# Generated deterministically by seda-macro-lef-normalizer-v1; recipe orfs-asap7-fakeram-m4-v1.
VERSION 5.8 ;
BUSBITCHARS "[]" ;
DIVIDERCHAR "/" ;

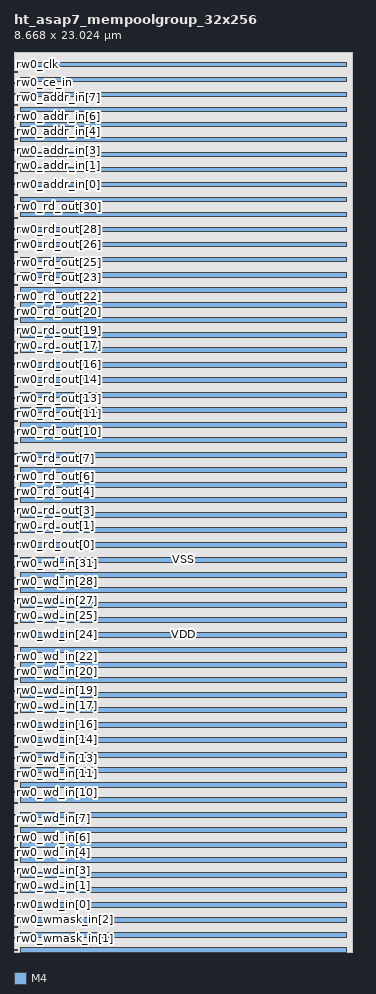
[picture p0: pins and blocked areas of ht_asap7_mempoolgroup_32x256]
MACRO ht_asap7_mempoolgroup_32x256
  FOREIGN ht_asap7_mempoolgroup_32x256 0 0 ;
  CLASS BLOCK ;
  ORIGIN 0 0 ;
  SIZE 8.668 BY 23.024 ;
  SYMMETRY X Y R90 ;
  PIN rw0_wmask_in[0]
    DIRECTION INPUT ;
    USE SIGNAL ;
    SHAPE ABUTMENT ;
    PORT
      LAYER M4 ;
      RECT 0.000 0.048 0.084 0.072 ;
    END
  END rw0_wmask_in[0]
  PIN rw0_wmask_in[1]
    DIRECTION INPUT ;
    USE SIGNAL ;
    SHAPE ABUTMENT ;
    PORT
      LAYER M4 ;
      RECT 0.000 0.336 0.084 0.360 ;
    END
  END rw0_wmask_in[1]
  PIN rw0_wmask_in[2]
    DIRECTION INPUT ;
    USE SIGNAL ;
    SHAPE ABUTMENT ;
    PORT
      LAYER M4 ;
      RECT 0.000 0.624 0.084 0.648 ;
    END
  END rw0_wmask_in[2]
  PIN rw0_wmask_in[3]
    DIRECTION INPUT ;
    USE SIGNAL ;
    SHAPE ABUTMENT ;
    PORT
      LAYER M4 ;
      RECT 0.000 0.912 0.084 0.936 ;
    END
  END rw0_wmask_in[3]
  PIN rw0_wd_in[0]
    DIRECTION INPUT ;
    USE SIGNAL ;
    SHAPE ABUTMENT ;
    PORT
      LAYER M4 ;
      RECT 0.000 1.200 0.084 1.224 ;
    END
  END rw0_wd_in[0]
  PIN rw0_wd_in[1]
    DIRECTION INPUT ;
    USE SIGNAL ;
    SHAPE ABUTMENT ;
    PORT
      LAYER M4 ;
      RECT 0.000 1.488 0.084 1.512 ;
    END
  END rw0_wd_in[1]
  PIN rw0_wd_in[2]
    DIRECTION INPUT ;
    USE SIGNAL ;
    SHAPE ABUTMENT ;
    PORT
      LAYER M4 ;
      RECT 0.000 1.776 0.084 1.800 ;
    END
  END rw0_wd_in[2]
  PIN rw0_wd_in[3]
    DIRECTION INPUT ;
    USE SIGNAL ;
    SHAPE ABUTMENT ;
    PORT
      LAYER M4 ;
      RECT 0.000 2.064 0.084 2.088 ;
    END
  END rw0_wd_in[3]
  PIN rw0_wd_in[4]
    DIRECTION INPUT ;
    USE SIGNAL ;
    SHAPE ABUTMENT ;
    PORT
      LAYER M4 ;
      RECT 0.000 2.352 0.084 2.376 ;
    END
  END rw0_wd_in[4]
  PIN rw0_wd_in[5]
    DIRECTION INPUT ;
    USE SIGNAL ;
    SHAPE ABUTMENT ;
    PORT
      LAYER M4 ;
      RECT 0.000 2.640 0.084 2.664 ;
    END
  END rw0_wd_in[5]
  PIN rw0_wd_in[6]
    DIRECTION INPUT ;
    USE SIGNAL ;
    SHAPE ABUTMENT ;
    PORT
      LAYER M4 ;
      RECT 0.000 2.928 0.084 2.952 ;
    END
  END rw0_wd_in[6]
  PIN rw0_wd_in[7]
    DIRECTION INPUT ;
    USE SIGNAL ;
    SHAPE ABUTMENT ;
    PORT
      LAYER M4 ;
      RECT 0.000 3.216 0.084 3.240 ;
    END
  END rw0_wd_in[7]
  PIN rw0_wd_in[8]
    DIRECTION INPUT ;
    USE SIGNAL ;
    SHAPE ABUTMENT ;
    PORT
      LAYER M4 ;
      RECT 0.000 3.504 0.084 3.528 ;
    END
  END rw0_wd_in[8]
  PIN rw0_wd_in[9]
    DIRECTION INPUT ;
    USE SIGNAL ;
    SHAPE ABUTMENT ;
    PORT
      LAYER M4 ;
      RECT 0.000 3.792 0.084 3.816 ;
    END
  END rw0_wd_in[9]
  PIN rw0_wd_in[10]
    DIRECTION INPUT ;
    USE SIGNAL ;
    SHAPE ABUTMENT ;
    PORT
      LAYER M4 ;
      RECT 0.000 4.080 0.084 4.104 ;
    END
  END rw0_wd_in[10]
  PIN rw0_wd_in[11]
    DIRECTION INPUT ;
    USE SIGNAL ;
    SHAPE ABUTMENT ;
    PORT
      LAYER M4 ;
      RECT 0.000 4.368 0.084 4.392 ;
    END
  END rw0_wd_in[11]
  PIN rw0_wd_in[12]
    DIRECTION INPUT ;
    USE SIGNAL ;
    SHAPE ABUTMENT ;
    PORT
      LAYER M4 ;
      RECT 0.000 4.656 0.084 4.680 ;
    END
  END rw0_wd_in[12]
  PIN rw0_wd_in[13]
    DIRECTION INPUT ;
    USE SIGNAL ;
    SHAPE ABUTMENT ;
    PORT
      LAYER M4 ;
      RECT 0.000 4.944 0.084 4.968 ;
    END
  END rw0_wd_in[13]
  PIN rw0_wd_in[14]
    DIRECTION INPUT ;
    USE SIGNAL ;
    SHAPE ABUTMENT ;
    PORT
      LAYER M4 ;
      RECT 0.000 5.232 0.084 5.256 ;
    END
  END rw0_wd_in[14]
  PIN rw0_wd_in[15]
    DIRECTION INPUT ;
    USE SIGNAL ;
    SHAPE ABUTMENT ;
    PORT
      LAYER M4 ;
      RECT 0.000 5.520 0.084 5.544 ;
    END
  END rw0_wd_in[15]
  PIN rw0_wd_in[16]
    DIRECTION INPUT ;
    USE SIGNAL ;
    SHAPE ABUTMENT ;
    PORT
      LAYER M4 ;
      RECT 0.000 5.808 0.084 5.832 ;
    END
  END rw0_wd_in[16]
  PIN rw0_wd_in[17]
    DIRECTION INPUT ;
    USE SIGNAL ;
    SHAPE ABUTMENT ;
    PORT
      LAYER M4 ;
      RECT 0.000 6.096 0.084 6.120 ;
    END
  END rw0_wd_in[17]
  PIN rw0_wd_in[18]
    DIRECTION INPUT ;
    USE SIGNAL ;
    SHAPE ABUTMENT ;
    PORT
      LAYER M4 ;
      RECT 0.000 6.384 0.084 6.408 ;
    END
  END rw0_wd_in[18]
  PIN rw0_wd_in[19]
    DIRECTION INPUT ;
    USE SIGNAL ;
    SHAPE ABUTMENT ;
    PORT
      LAYER M4 ;
      RECT 0.000 6.672 0.084 6.696 ;
    END
  END rw0_wd_in[19]
  PIN rw0_wd_in[20]
    DIRECTION INPUT ;
    USE SIGNAL ;
    SHAPE ABUTMENT ;
    PORT
      LAYER M4 ;
      RECT 0.000 6.960 0.084 6.984 ;
    END
  END rw0_wd_in[20]
  PIN rw0_wd_in[21]
    DIRECTION INPUT ;
    USE SIGNAL ;
    SHAPE ABUTMENT ;
    PORT
      LAYER M4 ;
      RECT 0.000 7.248 0.084 7.272 ;
    END
  END rw0_wd_in[21]
  PIN rw0_wd_in[22]
    DIRECTION INPUT ;
    USE SIGNAL ;
    SHAPE ABUTMENT ;
    PORT
      LAYER M4 ;
      RECT 0.000 7.536 0.084 7.560 ;
    END
  END rw0_wd_in[22]
  PIN rw0_wd_in[23]
    DIRECTION INPUT ;
    USE SIGNAL ;
    SHAPE ABUTMENT ;
    PORT
      LAYER M4 ;
      RECT 0.000 7.824 0.084 7.848 ;
    END
  END rw0_wd_in[23]
  PIN rw0_wd_in[24]
    DIRECTION INPUT ;
    USE SIGNAL ;
    SHAPE ABUTMENT ;
    PORT
      LAYER M4 ;
      RECT 0.000 8.112 0.084 8.136 ;
    END
  END rw0_wd_in[24]
  PIN rw0_wd_in[25]
    DIRECTION INPUT ;
    USE SIGNAL ;
    SHAPE ABUTMENT ;
    PORT
      LAYER M4 ;
      RECT 0.000 8.400 0.084 8.424 ;
    END
  END rw0_wd_in[25]
  PIN rw0_wd_in[26]
    DIRECTION INPUT ;
    USE SIGNAL ;
    SHAPE ABUTMENT ;
    PORT
      LAYER M4 ;
      RECT 0.000 8.688 0.084 8.712 ;
    END
  END rw0_wd_in[26]
  PIN rw0_wd_in[27]
    DIRECTION INPUT ;
    USE SIGNAL ;
    SHAPE ABUTMENT ;
    PORT
      LAYER M4 ;
      RECT 0.000 8.976 0.084 9.000 ;
    END
  END rw0_wd_in[27]
  PIN rw0_wd_in[28]
    DIRECTION INPUT ;
    USE SIGNAL ;
    SHAPE ABUTMENT ;
    PORT
      LAYER M4 ;
      RECT 0.000 9.264 0.084 9.288 ;
    END
  END rw0_wd_in[28]
  PIN rw0_wd_in[29]
    DIRECTION INPUT ;
    USE SIGNAL ;
    SHAPE ABUTMENT ;
    PORT
      LAYER M4 ;
      RECT 0.000 9.552 0.084 9.576 ;
    END
  END rw0_wd_in[29]
  PIN rw0_wd_in[30]
    DIRECTION INPUT ;
    USE SIGNAL ;
    SHAPE ABUTMENT ;
    PORT
      LAYER M4 ;
      RECT 0.000 9.840 0.084 9.864 ;
    END
  END rw0_wd_in[30]
  PIN rw0_wd_in[31]
    DIRECTION INPUT ;
    USE SIGNAL ;
    SHAPE ABUTMENT ;
    PORT
      LAYER M4 ;
      RECT 0.000 10.128 0.084 10.152 ;
    END
  END rw0_wd_in[31]
  PIN rw0_rd_out[0]
    DIRECTION OUTPUT ;
    USE SIGNAL ;
    SHAPE ABUTMENT ;
    PORT
      LAYER M4 ;
      RECT 0.000 10.416 0.084 10.440 ;
    END
  END rw0_rd_out[0]
  PIN rw0_rd_out[1]
    DIRECTION OUTPUT ;
    USE SIGNAL ;
    SHAPE ABUTMENT ;
    PORT
      LAYER M4 ;
      RECT 0.000 10.704 0.084 10.728 ;
    END
  END rw0_rd_out[1]
  PIN rw0_rd_out[2]
    DIRECTION OUTPUT ;
    USE SIGNAL ;
    SHAPE ABUTMENT ;
    PORT
      LAYER M4 ;
      RECT 0.000 10.992 0.084 11.016 ;
    END
  END rw0_rd_out[2]
  PIN rw0_rd_out[3]
    DIRECTION OUTPUT ;
    USE SIGNAL ;
    SHAPE ABUTMENT ;
    PORT
      LAYER M4 ;
      RECT 0.000 11.280 0.084 11.304 ;
    END
  END rw0_rd_out[3]
  PIN rw0_rd_out[4]
    DIRECTION OUTPUT ;
    USE SIGNAL ;
    SHAPE ABUTMENT ;
    PORT
      LAYER M4 ;
      RECT 0.000 11.568 0.084 11.592 ;
    END
  END rw0_rd_out[4]
  PIN rw0_rd_out[5]
    DIRECTION OUTPUT ;
    USE SIGNAL ;
    SHAPE ABUTMENT ;
    PORT
      LAYER M4 ;
      RECT 0.000 11.856 0.084 11.880 ;
    END
  END rw0_rd_out[5]
  PIN rw0_rd_out[6]
    DIRECTION OUTPUT ;
    USE SIGNAL ;
    SHAPE ABUTMENT ;
    PORT
      LAYER M4 ;
      RECT 0.000 12.144 0.084 12.168 ;
    END
  END rw0_rd_out[6]
  PIN rw0_rd_out[7]
    DIRECTION OUTPUT ;
    USE SIGNAL ;
    SHAPE ABUTMENT ;
    PORT
      LAYER M4 ;
      RECT 0.000 12.432 0.084 12.456 ;
    END
  END rw0_rd_out[7]
  PIN rw0_rd_out[8]
    DIRECTION OUTPUT ;
    USE SIGNAL ;
    SHAPE ABUTMENT ;
    PORT
      LAYER M4 ;
      RECT 0.000 12.720 0.084 12.744 ;
    END
  END rw0_rd_out[8]
  PIN rw0_rd_out[9]
    DIRECTION OUTPUT ;
    USE SIGNAL ;
    SHAPE ABUTMENT ;
    PORT
      LAYER M4 ;
      RECT 0.000 13.008 0.084 13.032 ;
    END
  END rw0_rd_out[9]
  PIN rw0_rd_out[10]
    DIRECTION OUTPUT ;
    USE SIGNAL ;
    SHAPE ABUTMENT ;
    PORT
      LAYER M4 ;
      RECT 0.000 13.296 0.084 13.320 ;
    END
  END rw0_rd_out[10]
  PIN rw0_rd_out[11]
    DIRECTION OUTPUT ;
    USE SIGNAL ;
    SHAPE ABUTMENT ;
    PORT
      LAYER M4 ;
      RECT 0.000 13.584 0.084 13.608 ;
    END
  END rw0_rd_out[11]
  PIN rw0_rd_out[12]
    DIRECTION OUTPUT ;
    USE SIGNAL ;
    SHAPE ABUTMENT ;
    PORT
      LAYER M4 ;
      RECT 0.000 13.872 0.084 13.896 ;
    END
  END rw0_rd_out[12]
  PIN rw0_rd_out[13]
    DIRECTION OUTPUT ;
    USE SIGNAL ;
    SHAPE ABUTMENT ;
    PORT
      LAYER M4 ;
      RECT 0.000 14.160 0.084 14.184 ;
    END
  END rw0_rd_out[13]
  PIN rw0_rd_out[14]
    DIRECTION OUTPUT ;
    USE SIGNAL ;
    SHAPE ABUTMENT ;
    PORT
      LAYER M4 ;
      RECT 0.000 14.448 0.084 14.472 ;
    END
  END rw0_rd_out[14]
  PIN rw0_rd_out[15]
    DIRECTION OUTPUT ;
    USE SIGNAL ;
    SHAPE ABUTMENT ;
    PORT
      LAYER M4 ;
      RECT 0.000 14.736 0.084 14.760 ;
    END
  END rw0_rd_out[15]
  PIN rw0_rd_out[16]
    DIRECTION OUTPUT ;
    USE SIGNAL ;
    SHAPE ABUTMENT ;
    PORT
      LAYER M4 ;
      RECT 0.000 15.024 0.084 15.048 ;
    END
  END rw0_rd_out[16]
  PIN rw0_rd_out[17]
    DIRECTION OUTPUT ;
    USE SIGNAL ;
    SHAPE ABUTMENT ;
    PORT
      LAYER M4 ;
      RECT 0.000 15.312 0.084 15.336 ;
    END
  END rw0_rd_out[17]
  PIN rw0_rd_out[18]
    DIRECTION OUTPUT ;
    USE SIGNAL ;
    SHAPE ABUTMENT ;
    PORT
      LAYER M4 ;
      RECT 0.000 15.600 0.084 15.624 ;
    END
  END rw0_rd_out[18]
  PIN rw0_rd_out[19]
    DIRECTION OUTPUT ;
    USE SIGNAL ;
    SHAPE ABUTMENT ;
    PORT
      LAYER M4 ;
      RECT 0.000 15.888 0.084 15.912 ;
    END
  END rw0_rd_out[19]
  PIN rw0_rd_out[20]
    DIRECTION OUTPUT ;
    USE SIGNAL ;
    SHAPE ABUTMENT ;
    PORT
      LAYER M4 ;
      RECT 0.000 16.176 0.084 16.200 ;
    END
  END rw0_rd_out[20]
  PIN rw0_rd_out[21]
    DIRECTION OUTPUT ;
    USE SIGNAL ;
    SHAPE ABUTMENT ;
    PORT
      LAYER M4 ;
      RECT 0.000 16.464 0.084 16.488 ;
    END
  END rw0_rd_out[21]
  PIN rw0_rd_out[22]
    DIRECTION OUTPUT ;
    USE SIGNAL ;
    SHAPE ABUTMENT ;
    PORT
      LAYER M4 ;
      RECT 0.000 16.752 0.084 16.776 ;
    END
  END rw0_rd_out[22]
  PIN rw0_rd_out[23]
    DIRECTION OUTPUT ;
    USE SIGNAL ;
    SHAPE ABUTMENT ;
    PORT
      LAYER M4 ;
      RECT 0.000 17.040 0.084 17.064 ;
    END
  END rw0_rd_out[23]
  PIN rw0_rd_out[24]
    DIRECTION OUTPUT ;
    USE SIGNAL ;
    SHAPE ABUTMENT ;
    PORT
      LAYER M4 ;
      RECT 0.000 17.328 0.084 17.352 ;
    END
  END rw0_rd_out[24]
  PIN rw0_rd_out[25]
    DIRECTION OUTPUT ;
    USE SIGNAL ;
    SHAPE ABUTMENT ;
    PORT
      LAYER M4 ;
      RECT 0.000 17.616 0.084 17.640 ;
    END
  END rw0_rd_out[25]
  PIN rw0_rd_out[26]
    DIRECTION OUTPUT ;
    USE SIGNAL ;
    SHAPE ABUTMENT ;
    PORT
      LAYER M4 ;
      RECT 0.000 17.904 0.084 17.928 ;
    END
  END rw0_rd_out[26]
  PIN rw0_rd_out[27]
    DIRECTION OUTPUT ;
    USE SIGNAL ;
    SHAPE ABUTMENT ;
    PORT
      LAYER M4 ;
      RECT 0.000 18.192 0.084 18.216 ;
    END
  END rw0_rd_out[27]
  PIN rw0_rd_out[28]
    DIRECTION OUTPUT ;
    USE SIGNAL ;
    SHAPE ABUTMENT ;
    PORT
      LAYER M4 ;
      RECT 0.000 18.480 0.084 18.504 ;
    END
  END rw0_rd_out[28]
  PIN rw0_rd_out[29]
    DIRECTION OUTPUT ;
    USE SIGNAL ;
    SHAPE ABUTMENT ;
    PORT
      LAYER M4 ;
      RECT 0.000 18.768 0.084 18.792 ;
    END
  END rw0_rd_out[29]
  PIN rw0_rd_out[30]
    DIRECTION OUTPUT ;
    USE SIGNAL ;
    SHAPE ABUTMENT ;
    PORT
      LAYER M4 ;
      RECT 0.000 19.056 0.084 19.080 ;
    END
  END rw0_rd_out[30]
  PIN rw0_rd_out[31]
    DIRECTION OUTPUT ;
    USE SIGNAL ;
    SHAPE ABUTMENT ;
    PORT
      LAYER M4 ;
      RECT 0.000 19.344 0.084 19.368 ;
    END
  END rw0_rd_out[31]
  PIN rw0_addr_in[0]
    DIRECTION INPUT ;
    USE SIGNAL ;
    SHAPE ABUTMENT ;
    PORT
      LAYER M4 ;
      RECT 0.000 19.632 0.084 19.656 ;
    END
  END rw0_addr_in[0]
  PIN rw0_addr_in[1]
    DIRECTION INPUT ;
    USE SIGNAL ;
    SHAPE ABUTMENT ;
    PORT
      LAYER M4 ;
      RECT 0.000 19.920 0.084 19.944 ;
    END
  END rw0_addr_in[1]
  PIN rw0_addr_in[2]
    DIRECTION INPUT ;
    USE SIGNAL ;
    SHAPE ABUTMENT ;
    PORT
      LAYER M4 ;
      RECT 0.000 20.208 0.084 20.232 ;
    END
  END rw0_addr_in[2]
  PIN rw0_addr_in[3]
    DIRECTION INPUT ;
    USE SIGNAL ;
    SHAPE ABUTMENT ;
    PORT
      LAYER M4 ;
      RECT 0.000 20.496 0.084 20.520 ;
    END
  END rw0_addr_in[3]
  PIN rw0_addr_in[4]
    DIRECTION INPUT ;
    USE SIGNAL ;
    SHAPE ABUTMENT ;
    PORT
      LAYER M4 ;
      RECT 0.000 20.784 0.084 20.808 ;
    END
  END rw0_addr_in[4]
  PIN rw0_addr_in[5]
    DIRECTION INPUT ;
    USE SIGNAL ;
    SHAPE ABUTMENT ;
    PORT
      LAYER M4 ;
      RECT 0.000 21.072 0.084 21.096 ;
    END
  END rw0_addr_in[5]
  PIN rw0_addr_in[6]
    DIRECTION INPUT ;
    USE SIGNAL ;
    SHAPE ABUTMENT ;
    PORT
      LAYER M4 ;
      RECT 0.000 21.360 0.084 21.384 ;
    END
  END rw0_addr_in[6]
  PIN rw0_addr_in[7]
    DIRECTION INPUT ;
    USE SIGNAL ;
    SHAPE ABUTMENT ;
    PORT
      LAYER M4 ;
      RECT 0.000 21.648 0.084 21.672 ;
    END
  END rw0_addr_in[7]
  PIN rw0_we_in
    DIRECTION INPUT ;
    USE SIGNAL ;
    SHAPE ABUTMENT ;
    PORT
      LAYER M4 ;
      RECT 0.000 21.936 0.084 21.960 ;
    END
  END rw0_we_in
  PIN rw0_ce_in
    DIRECTION INPUT ;
    USE SIGNAL ;
    SHAPE ABUTMENT ;
    PORT
      LAYER M4 ;
      RECT 0.000 22.224 0.084 22.248 ;
    END
  END rw0_ce_in
  PIN rw0_clk
    DIRECTION INPUT ;
    USE SIGNAL ;
    SHAPE ABUTMENT ;
    PORT
      LAYER M4 ;
      RECT 0.000 22.512 0.084 22.536 ;
    END
  END rw0_clk
  PIN VSS
    DIRECTION INOUT ;
    USE GROUND ;
    PORT
      LAYER M4 ;
      RECT 0.156 0.000 8.512 0.120 ;
      RECT 0.156 0.756 8.512 0.876 ;
      RECT 0.156 1.524 8.512 1.644 ;
      RECT 0.156 2.292 8.512 2.412 ;
      RECT 0.156 3.060 8.512 3.180 ;
      RECT 0.156 3.828 8.512 3.948 ;
      RECT 0.156 4.596 8.512 4.716 ;
      RECT 0.156 5.364 8.512 5.484 ;
      RECT 0.156 6.132 8.512 6.252 ;
      RECT 0.156 6.900 8.512 7.020 ;
      RECT 0.156 7.668 8.512 7.788 ;
      RECT 0.156 8.436 8.512 8.556 ;
      RECT 0.156 9.204 8.512 9.324 ;
      RECT 0.156 9.972 8.512 10.092 ;
      RECT 0.156 10.740 8.512 10.860 ;
      RECT 0.156 11.508 8.512 11.628 ;
      RECT 0.156 12.276 8.512 12.396 ;
      RECT 0.156 13.044 8.512 13.164 ;
      RECT 0.156 13.812 8.512 13.932 ;
      RECT 0.156 14.580 8.512 14.700 ;
      RECT 0.156 15.348 8.512 15.468 ;
      RECT 0.156 16.116 8.512 16.236 ;
      RECT 0.156 16.884 8.512 17.004 ;
      RECT 0.156 17.652 8.512 17.772 ;
      RECT 0.156 18.420 8.512 18.540 ;
      RECT 0.156 19.188 8.512 19.308 ;
      RECT 0.156 19.956 8.512 20.076 ;
      RECT 0.156 20.724 8.512 20.844 ;
      RECT 0.156 21.492 8.512 21.612 ;
      RECT 0.156 22.260 8.512 22.380 ;
    END
  END VSS
  PIN VDD
    DIRECTION INOUT ;
    USE POWER ;
    PORT
      LAYER M4 ;
      RECT 0.156 0.372 8.512 0.492 ;
      RECT 0.156 1.140 8.512 1.260 ;
      RECT 0.156 1.908 8.512 2.028 ;
      RECT 0.156 2.676 8.512 2.796 ;
      RECT 0.156 3.444 8.512 3.564 ;
      RECT 0.156 4.212 8.512 4.332 ;
      RECT 0.156 4.980 8.512 5.100 ;
      RECT 0.156 5.748 8.512 5.868 ;
      RECT 0.156 6.516 8.512 6.636 ;
      RECT 0.156 7.284 8.512 7.404 ;
      RECT 0.156 8.052 8.512 8.172 ;
      RECT 0.156 8.820 8.512 8.940 ;
      RECT 0.156 9.588 8.512 9.708 ;
      RECT 0.156 10.356 8.512 10.476 ;
      RECT 0.156 11.124 8.512 11.244 ;
      RECT 0.156 11.892 8.512 12.012 ;
      RECT 0.156 12.660 8.512 12.780 ;
      RECT 0.156 13.428 8.512 13.548 ;
      RECT 0.156 14.196 8.512 14.316 ;
      RECT 0.156 14.964 8.512 15.084 ;
      RECT 0.156 15.732 8.512 15.852 ;
      RECT 0.156 16.500 8.512 16.620 ;
      RECT 0.156 17.268 8.512 17.388 ;
      RECT 0.156 18.036 8.512 18.156 ;
      RECT 0.156 18.804 8.512 18.924 ;
      RECT 0.156 19.572 8.512 19.692 ;
      RECT 0.156 20.340 8.512 20.460 ;
      RECT 0.156 21.108 8.512 21.228 ;
      RECT 0.156 21.876 8.512 21.996 ;
      RECT 0.156 22.644 8.512 22.764 ;
    END
  END VDD
  OBS
    LAYER M1 ;
    RECT 0 0 8.668 23.024 ;
    LAYER M2 ;
    RECT 0 0 8.668 23.024 ;
    LAYER M3 ;
    RECT 0 0 8.668 23.024 ;
  END
END ht_asap7_mempoolgroup_32x256

END LIBRARY
